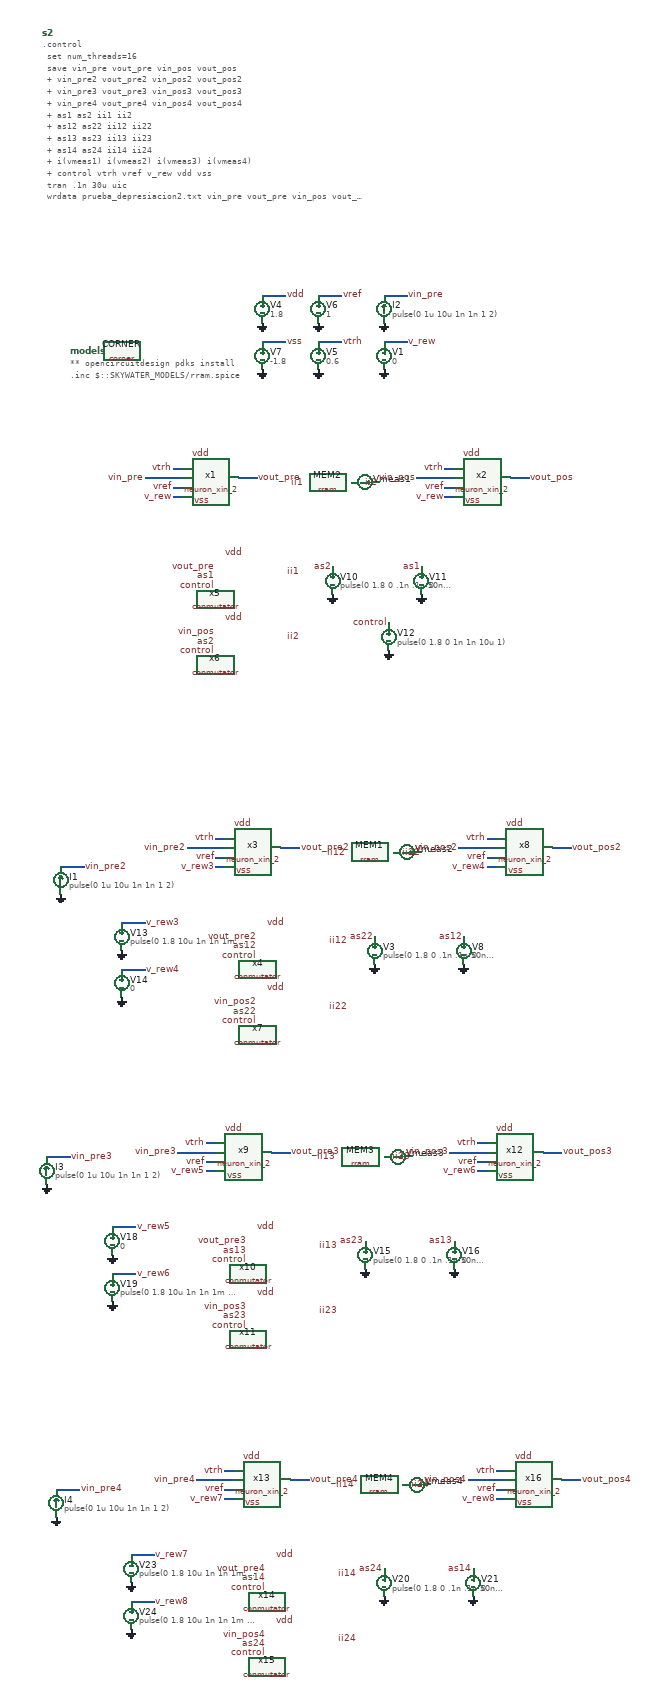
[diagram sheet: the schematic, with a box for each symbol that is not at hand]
v {xschem version=3.4.5 file_version=1.2
}
G {}
K {}
V {}
S {}
E {}
B 2 -2720 -470 -2300 -270 {flags=graph
y1=0
y2=1.8
ypos1=0
ypos2=2
divy=5
subdivy=1
unity=1
x1=1e-12
x2=3e-05
divx=5
subdivx=1
xlabmag=1.0
ylabmag=1.0
node="control
vtrh
vrew"
color="4 6 7"
dataset=-1
unitx=1
logx=0
logy=0
}
B 2 -2720 -270 -2300 -70 {flags=graph
y1=0
y2=0.01
ypos1=0
ypos2=2
divy=5
subdivy=1
unity=1
x1=1e-12
x2=3e-05
divx=5
subdivx=1
xlabmag=1.0
ylabmag=1.0
node=v_rew
color=7
dataset=-1
unitx=1
logx=0
logy=0
}
B 2 -2720 -70 -2300 130 {flags=graph
y1=0
y2=3
ypos1=0
ypos2=2
divy=5
subdivy=1
unity=1
x1=1e-12
x2=3e-05
divx=5
subdivx=1
xlabmag=1.0
ylabmag=1.0
node="as1
as2"
color="4 7"
dataset=-1
unitx=1
logx=0
logy=0
}
B 2 -1960 70 -1540 270 {flags=graph
y1=-1.2e-06
y2=7.4e-07
ypos1=0
ypos2=2
divy=5
subdivy=1
unity=1
x1=1e-12
x2=3e-05
divx=5
subdivx=1
xlabmag=1.0
ylabmag=1.0


dataset=-1
unitx=1
logx=0
logy=0


color=8
node=I(vmeas1)}
B 2 -1220 -130 -420 270 {flags=graph
y1=48e3
y2=56e3
ypos1=0
ypos2=2
divy=5
subdivy=1
unity=1
x1=1e-12
x2=3e-05
divx=5
subdivx=1
xlabmag=1.0
ylabmag=1.0


dataset=-1
unitx=1
logx=0
logy=0







color=9
node="\\"ii1 ii2 - i(vmeas1) /\\""
linewidth_mult=2}
B 2 -1220 -930 -420 -530 {flags=graph
y1=0
y2=1.8
ypos1=0
ypos2=2
divy=5
subdivy=1
unity=1

x2=3e-05
divx=5
subdivx=1
xlabmag=1.0
ylabmag=1.0
node=vout_pre
color=4
dataset=-1
unitx=1
logx=0
logy=0

x1=1e-12
linewidth_mult=2}
B 2 -1220 -530 -420 -130 {flags=graph

y2=1.8
ypos1=0
ypos2=2
divy=5
subdivy=1
unity=1

x2=3e-05
divx=5
subdivx=1
xlabmag=1.0
ylabmag=1.0
node=vout_pos
color=4
dataset=-1
unitx=1
logx=0
logy=0

y1=0
linewidth_mult=2
x1=1e-12}
B 2 -420 -130 380 270 {flags=graph
y1=48e3
y2=56e3
ypos1=0
ypos2=2
divy=5
subdivy=1
unity=1

x2=3e-05
divx=5
subdivx=1
xlabmag=1.0
ylabmag=1.0


dataset=-1
unitx=1
logx=0
logy=0







color=9
node="\\"ii12 ii22 - i(vmeas2) /\\""
linewidth_mult=2
x1=1e-12}
B 2 -420 -930 380 -530 {flags=graph
y1=0.44
y2=1.7
ypos1=0
ypos2=2
divy=5
subdivy=1
unity=1

x2=3e-05
divx=5
subdivx=1
xlabmag=1.0
ylabmag=1.0
node=vout_pre2
color=4
dataset=-1
unitx=1
logx=0
logy=0

x1=1e-12
linewidth_mult=2}
B 2 -420 -530 380 -130 {flags=graph

y2=1.8
ypos1=0
ypos2=2
divy=5
subdivy=1
unity=1

x2=3e-05
divx=5
subdivx=1
xlabmag=1.0
ylabmag=1.0
node=vout_pos2
color=4
dataset=-1
unitx=1
logx=0
logy=0

y1=0
linewidth_mult=2
x1=1e-12}
B 2 380 -130 1180 270 {flags=graph
y1=48e3
y2=56e3
ypos1=0
ypos2=2
divy=5
subdivy=1
unity=1
x1=1e-12
x2=3e-05
divx=5
subdivx=1
xlabmag=1.0
ylabmag=1.0


dataset=-1
unitx=1
logx=0
logy=0







color=9
node="\\"ii13 ii23 - i(vmeas3) /\\""
linewidth_mult=2}
B 2 380 -930 1180 -530 {flags=graph
y1=0
y2=1.8
ypos1=0
ypos2=2
divy=5
subdivy=1
unity=1

x2=3e-05
divx=5
subdivx=1
xlabmag=1.0
ylabmag=1.0
node=vout_pre3
color=4
dataset=-1
unitx=1
logx=0
logy=0

x1=1e-12
linewidth_mult=2}
B 2 380 -530 1180 -130 {flags=graph

y2=1.8
ypos1=0
ypos2=2
divy=5
subdivy=1
unity=1

x2=3e-05
divx=5
subdivx=1
xlabmag=1.0
ylabmag=1.0
node=vout_pos3
color=4
dataset=-1
unitx=1
logx=0
logy=0

y1=0
linewidth_mult=2
x1=1e-12}
B 2 1180 -130 1980 270 {flags=graph
y1=48e3
y2=56e3
ypos1=0
ypos2=2
divy=5
subdivy=1
unity=1
x1=1e-12
x2=3e-05
divx=5
subdivx=1
xlabmag=1.0
ylabmag=1.0


dataset=-1
unitx=1
logx=0
logy=0







color=9
node="\\"ii14 ii24 - i(vmeas4) /\\""
linewidth_mult=2}
B 2 1180 -930 1980 -530 {flags=graph
y1=0
y2=1.8
ypos1=0
ypos2=2
divy=5
subdivy=1
unity=1

x2=3e-05
divx=5
subdivx=1
xlabmag=1.0
ylabmag=1.0
node=vout_pre4
color=4
dataset=-1
unitx=1
logx=0
logy=0

x1=1e-12
linewidth_mult=2}
B 2 1180 -530 1980 -130 {flags=graph

y2=1.8
ypos1=0
ypos2=2
divy=5
subdivy=1
unity=1

x2=3e-05
divx=5
subdivx=1
xlabmag=1.0
ylabmag=1.0
node=vout_pos4
color=4
dataset=-1
unitx=1
logx=0
logy=0

y1=0
linewidth_mult=2
x1=1e-12}
N -2130 -320 -2110 -320 {
lab=vref}
N -1940 -730 -1890 -730 {
lab=vdd}
N -1820 -630 -1770 -630 {
lab=vtrh}
N -1820 -730 -1770 -730 {
lab=vref}
N -1940 -630 -1890 -630 {
lab=vss}
N -1680 -630 -1630 -630 {
lab=v_rew}
N -2130 -360 -2110 -360 {
lab=vtrh}
N -2130 -300 -2110 -300 {
lab=v_rew}
N -2190 -340 -2110 -340 {
lab=vin_pre}
N -1990 -340 -1950 -340 {
lab=vout_pre}
N -1550 -320 -1530 -320 {
lab=vref}
N -1550 -360 -1530 -360 {
lab=vtrh}
N -1550 -300 -1530 -300 {
lab=v_rew}
N -1610 -340 -1530 -340 {
lab=vin_pos}
N -1410 -340 -1370 -340 {
lab=vout_pos}
N -1680 -730 -1630 -730 {
lab=vin_pre}
N -2040 470 -2020 470 {
lab=vref}
N -2040 430 -2020 430 {
lab=vtrh}
N -2040 490 -2020 490 {
lab=v_rew3}
N -2100 450 -2020 450 {
lab=vin_pre2}
N -1900 450 -1860 450 {
lab=vout_pre2}
N -1460 470 -1440 470 {
lab=vref}
N -1460 430 -1440 430 {
lab=vtrh}
N -1460 490 -1440 490 {
lab=v_rew4}
N -1520 450 -1440 450 {
lab=vin_pos2}
N -1320 450 -1280 450 {
lab=vout_pos2}
N -2240 610 -2190 610 {
lab=v_rew3}
N -2240 710 -2190 710 {
lab=v_rew4}
N -2060 1120 -2040 1120 {
lab=vref}
N -2060 1080 -2040 1080 {
lab=vtrh}
N -2060 1140 -2040 1140 {
lab=v_rew5}
N -2120 1100 -2040 1100 {
lab=vin_pre3}
N -1920 1100 -1880 1100 {
lab=vout_pre3}
N -1480 1120 -1460 1120 {
lab=vref}
N -1480 1080 -1460 1080 {
lab=vtrh}
N -1480 1140 -1460 1140 {
lab=v_rew6}
N -1540 1100 -1460 1100 {
lab=vin_pos3}
N -1340 1100 -1300 1100 {
lab=vout_pos3}
N -2260 1260 -2210 1260 {
lab=v_rew5}
N -2260 1360 -2210 1360 {
lab=v_rew6}
N -2020 1820 -2000 1820 {
lab=vref}
N -2020 1780 -2000 1780 {
lab=vtrh}
N -2020 1840 -2000 1840 {
lab=v_rew7}
N -2080 1800 -2000 1800 {
lab=vin_pre4}
N -1880 1800 -1840 1800 {
lab=vout_pre4}
N -1440 1820 -1420 1820 {
lab=vref}
N -1440 1780 -1420 1780 {
lab=vtrh}
N -1440 1840 -1420 1840 {
lab=v_rew8}
N -1500 1800 -1420 1800 {
lab=vin_pos4}
N -1300 1800 -1260 1800 {
lab=vout_pos4}
N -2220 1960 -2170 1960 {
lab=v_rew7}
N -2220 2060 -2170 2060 {
lab=v_rew8}
N -2370 490 -2320 490 {
lab=vin_pre2}
N -2400 1110 -2350 1110 {
lab=vin_pre3}
N -2380 1820 -2330 1820 {
lab=vin_pre4}
C {/home/user/Documentos/neuron_xin_2.sym} -2050 -340 0 0 {name=x1}
C {devices/code_shown.sym} -2410 -1290 0 0 {name=s2 only_toplevel=false value="
.control
 set num_threads=16
 save vin_pre vout_pre vin_pos vout_pos
 + vin_pre2 vout_pre2 vin_pos2 vout_pos2
 + vin_pre3 vout_pre3 vin_pos3 vout_pos3
 + vin_pre4 vout_pre4 vin_pos4 vout_pos4
 + as1  as2  ii1  ii2
 + as12 as22 ii12 ii22
 + as13 as23 ii13 ii23
 + as14 as24 ii14 ii24
 + i(vmeas1) i(vmeas2) i(vmeas3) i(vmeas4)
 + control vtrh vref v_rew vdd vss
 tran .1n 30u uic
 wrdata prueba_depresiacion2.txt vin_pre vout_pre vin_pos vout_pos
 + vin_pre2 vout_pre2 vin_pos2 vout_pos2
 + vin_pre3 vout_pre3 vin_pos3 vout_pos3
 + vin_pre4 vout_pre4 vin_pos4 vout_pos4
 + as1  as2  ii1  ii2
 + as12 as22 ii12 ii22
 + as13 as23 ii13 ii23
 + as14 as24 ii14 ii24
 + i(vmeas1) i(vmeas2) i(vmeas3) i(vmeas4)
 write prueba_rewNeuron_depresiacion2.raw
.endc


" }
C {devices/lab_wire.sym} -2130 -320 0 0 {name=p54 sig_type=std_logic lab=vref}
C {devices/lab_wire.sym} -2050 -390 0 0 {name=p56 sig_type=std_logic lab=vdd}
C {devices/vsource.sym} -1940 -700 0 0 {name=V4 value=1.8}
C {devices/gnd.sym} -1940 -670 0 0 {name=l9 lab=GND}
C {devices/lab_wire.sym} -1890 -730 0 1 {name=p61 sig_type=std_logic lab=vdd}
C {devices/vsource.sym} -1820 -600 0 0 {name=V5 value=0.6}
C {devices/gnd.sym} -1820 -570 0 0 {name=l10 lab=GND}
C {devices/lab_wire.sym} -1770 -630 0 1 {name=p63 sig_type=std_logic lab=vtrh}
C {devices/vsource.sym} -1820 -700 0 0 {name=V6 value=1}
C {devices/gnd.sym} -1820 -670 0 0 {name=l11 lab=GND}
C {devices/lab_wire.sym} -1770 -730 0 1 {name=p64 sig_type=std_logic lab=vref}
C {devices/lab_wire.sym} -1950 -340 0 1 {name=p70 sig_type=std_logic lab=vout_pre}
C {devices/vsource.sym} -1940 -600 0 0 {name=V7 value=-1.8}
C {devices/gnd.sym} -1940 -570 0 0 {name=l13 lab=GND}
C {devices/lab_wire.sym} -1890 -630 0 1 {name=p72 sig_type=std_logic lab=vss}
C {devices/vsource.sym} -1680 -600 0 0 {name=V1 value=0}
C {devices/gnd.sym} -1680 -570 0 0 {name=l2 lab=GND}
C {devices/lab_wire.sym} -1630 -630 0 1 {name=p5 sig_type=std_logic lab=v_rew}
C {devices/lab_wire.sym} -2190 -340 0 0 {name=p7 sig_type=std_logic lab=vin_pre}
C {devices/lab_wire.sym} -2130 -360 0 0 {name=p8 sig_type=std_logic lab=vtrh}
C {devices/lab_wire.sym} -2050 -290 2 1 {name=p9 sig_type=std_logic lab=vss}
C {devices/lab_wire.sym} -2130 -300 0 0 {name=p1 sig_type=std_logic lab=v_rew}
C {sky130_fd_pr/corner.sym} -2240 -610 0 0 {name=CORNER only_toplevel=true corner=tt}
C {devices/code.sym} -2350 -610 0 0 {name=models
only_toplevel=false
format ="tcleval( @value ) "
value="** opencircuitdesign pdks install
.inc $::SKYWATER_MODELS/rram.spice"
spice_ignore=false}
C {devices/gnd.sym} -1790 -90 0 0 {name=l7 lab=GND}
C {devices/vsource.sym} -1790 -120 0 0 {name=V10 value="pulse(0 1.8 0 .1n .1n 50n 100n 100)"}
C {devices/gnd.sym} -1600 -90 0 0 {name=l12 lab=GND}
C {devices/vsource.sym} -1600 -120 0 0 {name=V11 value=0}
C {devices/gnd.sym} -1670 30 0 0 {name=l14 lab=GND}
C {devices/vsource.sym} -1670 0 0 0 {name=V12 value="pulse(0 1.8 0 1n 1n 10u 1)"}
C {devices/lab_wire.sym} -1670 -30 0 0 {name=p32 sig_type=std_logic lab=control
}
C {/home/user/Documentos/conmutator.sym} -2040 -80 0 0 {name=x5}
C {devices/lab_wire.sym} -2040 -110 0 0 {name=p33 sig_type=std_logic lab=control
}
C {devices/lab_wire.sym} -2040 -150 0 0 {name=p34 sig_type=std_logic lab=vout_pre}
C {devices/lab_wire.sym} -2040 -130 0 0 {name=p35 sig_type=std_logic lab=as1
}
C {devices/lab_wire.sym} -1980 -180 0 0 {name=p36 sig_type=std_logic lab=vdd}
C {devices/lab_wire.sym} -1890 -140 0 1 {name=p37 sig_type=std_logic lab=ii1}
C {devices/lab_wire.sym} -1600 -150 0 0 {name=p39 sig_type=std_logic lab=as1
}
C {devices/lab_wire.sym} -1790 -150 0 0 {name=p41 sig_type=std_logic lab=as2
}
C {/home/user/Documentos/conmutator.sym} -2040 60 0 0 {name=x6}
C {devices/lab_wire.sym} -2040 30 0 0 {name=p42 sig_type=std_logic lab=control
}
C {devices/lab_wire.sym} -2040 -10 0 0 {name=p43 sig_type=std_logic lab=vin_pos}
C {devices/lab_wire.sym} -2040 10 0 0 {name=p44 sig_type=std_logic lab=as2}
C {devices/lab_wire.sym} -1980 -40 0 0 {name=p45 sig_type=std_logic lab=vdd}
C {devices/lab_wire.sym} -1890 0 0 1 {name=p46 sig_type=std_logic lab=ii2}
C {sky130_fd_pr/rram.sym} -1800 -330 3 0 {name=MEM2
model=rram
spiceprefix=X}
C {devices/ammeter.sym} -1720 -330 3 1 {name=Vmeas1 savecurrent=true spice_ignore=0}
C {devices/lab_wire.sym} -1850 -330 0 0 {name=p67 sig_type=std_logic lab=ii1}
C {devices/lab_wire.sym} -1690 -330 0 0 {name=p68 sig_type=std_logic lab=ii2}
C {/home/user/Documentos/neuron_xin_2.sym} -1470 -340 0 0 {name=x2}
C {devices/lab_wire.sym} -1550 -320 0 0 {name=p2 sig_type=std_logic lab=vref}
C {devices/lab_wire.sym} -1470 -390 0 0 {name=p3 sig_type=std_logic lab=vdd}
C {devices/lab_wire.sym} -1370 -340 0 1 {name=p4 sig_type=std_logic lab=vout_pos}
C {devices/lab_wire.sym} -1610 -340 0 0 {name=p6 sig_type=std_logic lab=vin_pos}
C {devices/lab_wire.sym} -1550 -360 0 0 {name=p10 sig_type=std_logic lab=vtrh}
C {devices/lab_wire.sym} -1470 -290 2 1 {name=p11 sig_type=std_logic lab=vss}
C {devices/lab_wire.sym} -1550 -300 0 0 {name=p12 sig_type=std_logic lab=v_rew}
C {devices/gnd.sym} -1680 -670 0 0 {name=l15 lab=GND}
C {devices/lab_wire.sym} -1630 -730 0 1 {name=p85 sig_type=std_logic lab=vin_pre}
C {devices/isource.sym} -1680 -700 2 1 {name=I2 value="pulse(0 1u 10u 1n 1n 1 2)" }
C {/home/user/Documentos/neuron_xin_2.sym} -1960 450 0 0 {name=x3}
C {devices/lab_wire.sym} -2040 470 0 0 {name=p14 sig_type=std_logic lab=vref}
C {devices/lab_wire.sym} -1960 400 0 0 {name=p15 sig_type=std_logic lab=vdd}
C {devices/lab_wire.sym} -1860 450 0 1 {name=p16 sig_type=std_logic lab=vout_pre2}
C {devices/lab_wire.sym} -2100 450 0 0 {name=p17 sig_type=std_logic lab=vin_pre2}
C {devices/lab_wire.sym} -2040 430 0 0 {name=p18 sig_type=std_logic lab=vtrh}
C {devices/lab_wire.sym} -1960 500 2 1 {name=p19 sig_type=std_logic lab=vss}
C {devices/lab_wire.sym} -2040 490 0 0 {name=p20 sig_type=std_logic lab=v_rew3}
C {devices/gnd.sym} -1700 700 0 0 {name=l3 lab=GND}
C {devices/vsource.sym} -1700 670 0 0 {name=V3 value="pulse(0 1.8 0 .1n .1n 50n 100n 100)"}
C {devices/gnd.sym} -1510 700 0 0 {name=l4 lab=GND}
C {devices/vsource.sym} -1510 670 0 0 {name=V8 value=0}
C {/home/user/Documentos/conmutator.sym} -1950 710 0 0 {name=x4}
C {devices/lab_wire.sym} -1950 680 0 0 {name=p22 sig_type=std_logic lab=control
}
C {devices/lab_wire.sym} -1950 640 0 0 {name=p23 sig_type=std_logic lab=vout_pre2}
C {devices/lab_wire.sym} -1950 660 0 0 {name=p24 sig_type=std_logic lab=as12
}
C {devices/lab_wire.sym} -1890 610 0 0 {name=p25 sig_type=std_logic lab=vdd}
C {devices/lab_wire.sym} -1800 650 0 1 {name=p26 sig_type=std_logic lab=ii12}
C {devices/lab_wire.sym} -1510 640 0 0 {name=p27 sig_type=std_logic lab=as12
}
C {devices/lab_wire.sym} -1700 640 0 0 {name=p28 sig_type=std_logic lab=as22
}
C {/home/user/Documentos/conmutator.sym} -1950 850 0 0 {name=x7}
C {devices/lab_wire.sym} -1950 820 0 0 {name=p29 sig_type=std_logic lab=control
}
C {devices/lab_wire.sym} -1950 780 0 0 {name=p30 sig_type=std_logic lab=vin_pos2}
C {devices/lab_wire.sym} -1950 800 0 0 {name=p31 sig_type=std_logic lab=as22}
C {devices/lab_wire.sym} -1890 750 0 0 {name=p38 sig_type=std_logic lab=vdd}
C {devices/lab_wire.sym} -1800 790 0 1 {name=p40 sig_type=std_logic lab=ii22}
C {sky130_fd_pr/rram.sym} -1710 460 3 1 {name=MEM1
model=rram
spiceprefix=X}
C {devices/ammeter.sym} -1630 460 3 1 {name=Vmeas2 savecurrent=true spice_ignore=0}
C {devices/lab_wire.sym} -1760 460 0 0 {name=p47 sig_type=std_logic lab=ii12}
C {devices/lab_wire.sym} -1600 460 0 0 {name=p48 sig_type=std_logic lab=ii22}
C {/home/user/Documentos/neuron_xin_2.sym} -1380 450 0 0 {name=x8}
C {devices/lab_wire.sym} -1460 470 0 0 {name=p49 sig_type=std_logic lab=vref}
C {devices/lab_wire.sym} -1380 400 0 0 {name=p50 sig_type=std_logic lab=vdd}
C {devices/lab_wire.sym} -1280 450 0 1 {name=p51 sig_type=std_logic lab=vout_pos2}
C {devices/lab_wire.sym} -1520 450 0 0 {name=p52 sig_type=std_logic lab=vin_pos2}
C {devices/lab_wire.sym} -1460 430 0 0 {name=p53 sig_type=std_logic lab=vtrh}
C {devices/lab_wire.sym} -1380 500 2 1 {name=p55 sig_type=std_logic lab=vss}
C {devices/lab_wire.sym} -1460 490 0 0 {name=p57 sig_type=std_logic lab=v_rew4}
C {devices/vsource.sym} -2240 640 0 0 {name=V13 value="pulse(0 1.8 10u 1n 1n 1m 2m)"}
C {devices/gnd.sym} -2240 670 0 0 {name=l6 lab=GND}
C {devices/lab_wire.sym} -2190 610 0 1 {name=p58 sig_type=std_logic lab=v_rew3}
C {devices/vsource.sym} -2240 740 0 0 {name=V14 value=0}
C {devices/gnd.sym} -2240 770 0 0 {name=l8 lab=GND}
C {devices/lab_wire.sym} -2190 710 0 1 {name=p59 sig_type=std_logic lab=v_rew4}
C {/home/user/Documentos/neuron_xin_2.sym} -1980 1100 0 0 {name=x9}
C {devices/lab_wire.sym} -2060 1120 0 0 {name=p60 sig_type=std_logic lab=vref}
C {devices/lab_wire.sym} -1980 1050 0 0 {name=p62 sig_type=std_logic lab=vdd}
C {devices/lab_wire.sym} -1880 1100 0 1 {name=p65 sig_type=std_logic lab=vout_pre3}
C {devices/lab_wire.sym} -2120 1100 0 0 {name=p66 sig_type=std_logic lab=vin_pre3}
C {devices/lab_wire.sym} -2060 1080 0 0 {name=p69 sig_type=std_logic lab=vtrh}
C {devices/lab_wire.sym} -1980 1150 2 1 {name=p71 sig_type=std_logic lab=vss}
C {devices/lab_wire.sym} -2060 1140 0 0 {name=p73 sig_type=std_logic lab=v_rew5}
C {devices/gnd.sym} -1720 1350 0 0 {name=l16 lab=GND}
C {devices/vsource.sym} -1720 1320 0 0 {name=V15 value="pulse(0 1.8 0 .1n .1n 50n 100n 100)"}
C {devices/gnd.sym} -1530 1350 0 0 {name=l17 lab=GND}
C {devices/vsource.sym} -1530 1320 0 0 {name=V16 value=0}
C {/home/user/Documentos/conmutator.sym} -1970 1360 0 0 {name=x10}
C {devices/lab_wire.sym} -1970 1330 0 0 {name=p75 sig_type=std_logic lab=control
}
C {devices/lab_wire.sym} -1970 1290 0 0 {name=p76 sig_type=std_logic lab=vout_pre3}
C {devices/lab_wire.sym} -1970 1310 0 0 {name=p77 sig_type=std_logic lab=as13
}
C {devices/lab_wire.sym} -1910 1260 0 0 {name=p78 sig_type=std_logic lab=vdd}
C {devices/lab_wire.sym} -1820 1300 0 1 {name=p79 sig_type=std_logic lab=ii13}
C {devices/lab_wire.sym} -1530 1290 0 0 {name=p80 sig_type=std_logic lab=as13}
C {devices/lab_wire.sym} -1720 1290 0 0 {name=p81 sig_type=std_logic lab=as23
}
C {/home/user/Documentos/conmutator.sym} -1970 1500 0 0 {name=x11}
C {devices/lab_wire.sym} -1970 1470 0 0 {name=p82 sig_type=std_logic lab=control
}
C {devices/lab_wire.sym} -1970 1430 0 0 {name=p83 sig_type=std_logic lab=vin_pos3}
C {devices/lab_wire.sym} -1970 1450 0 0 {name=p84 sig_type=std_logic lab=as23}
C {devices/lab_wire.sym} -1910 1400 0 0 {name=p86 sig_type=std_logic lab=vdd}
C {devices/lab_wire.sym} -1820 1440 0 1 {name=p87 sig_type=std_logic lab=ii23}
C {sky130_fd_pr/rram.sym} -1730 1110 3 1 {name=MEM3
model=rram
spiceprefix=X}
C {devices/ammeter.sym} -1650 1110 3 1 {name=Vmeas3 savecurrent=true spice_ignore=0}
C {devices/lab_wire.sym} -1780 1110 0 0 {name=p88 sig_type=std_logic lab=ii13}
C {devices/lab_wire.sym} -1620 1110 0 0 {name=p89 sig_type=std_logic lab=ii23}
C {/home/user/Documentos/neuron_xin_2.sym} -1400 1100 0 0 {name=x12}
C {devices/lab_wire.sym} -1480 1120 0 0 {name=p90 sig_type=std_logic lab=vref}
C {devices/lab_wire.sym} -1400 1050 0 0 {name=p91 sig_type=std_logic lab=vdd}
C {devices/lab_wire.sym} -1300 1100 0 1 {name=p92 sig_type=std_logic lab=vout_pos3}
C {devices/lab_wire.sym} -1540 1100 0 0 {name=p93 sig_type=std_logic lab=vin_pos3}
C {devices/lab_wire.sym} -1480 1080 0 0 {name=p94 sig_type=std_logic lab=vtrh}
C {devices/lab_wire.sym} -1400 1150 2 1 {name=p95 sig_type=std_logic lab=vss}
C {devices/lab_wire.sym} -1480 1140 0 0 {name=p96 sig_type=std_logic lab=v_rew6}
C {devices/vsource.sym} -2260 1290 0 0 {name=V18 value=0}
C {devices/gnd.sym} -2260 1320 0 0 {name=l19 lab=GND}
C {devices/lab_wire.sym} -2210 1260 0 1 {name=p97 sig_type=std_logic lab=v_rew5}
C {devices/vsource.sym} -2260 1390 0 0 {name=V19 value="pulse(0 1.8 10u 1n 1n 1m 2m)"}
C {devices/gnd.sym} -2260 1420 0 0 {name=l20 lab=GND}
C {devices/lab_wire.sym} -2210 1360 0 1 {name=p98 sig_type=std_logic lab=v_rew6}
C {/home/user/Documentos/neuron_xin_2.sym} -1940 1800 0 0 {name=x13}
C {devices/lab_wire.sym} -2020 1820 0 0 {name=p99 sig_type=std_logic lab=vref}
C {devices/lab_wire.sym} -1940 1750 0 0 {name=p100 sig_type=std_logic lab=vdd}
C {devices/lab_wire.sym} -1840 1800 0 1 {name=p101 sig_type=std_logic lab=vout_pre4}
C {devices/lab_wire.sym} -2080 1800 0 0 {name=p102 sig_type=std_logic lab=vin_pre4}
C {devices/lab_wire.sym} -2020 1780 0 0 {name=p103 sig_type=std_logic lab=vtrh}
C {devices/lab_wire.sym} -1940 1850 2 1 {name=p104 sig_type=std_logic lab=vss}
C {devices/lab_wire.sym} -2020 1840 0 0 {name=p105 sig_type=std_logic lab=v_rew7}
C {devices/gnd.sym} -1680 2050 0 0 {name=l21 lab=GND}
C {devices/vsource.sym} -1680 2020 0 0 {name=V20 value="pulse(0 1.8 0 .1n .1n 50n 100n 100)"}
C {devices/gnd.sym} -1490 2050 0 0 {name=l22 lab=GND}
C {devices/vsource.sym} -1490 2020 0 0 {name=V21 value=0}
C {/home/user/Documentos/conmutator.sym} -1930 2060 0 0 {name=x14}
C {devices/lab_wire.sym} -1930 2030 0 0 {name=p107 sig_type=std_logic lab=control
}
C {devices/lab_wire.sym} -1930 1990 0 0 {name=p108 sig_type=std_logic lab=vout_pre4}
C {devices/lab_wire.sym} -1930 2010 0 0 {name=p109 sig_type=std_logic lab=as14
}
C {devices/lab_wire.sym} -1870 1960 0 0 {name=p110 sig_type=std_logic lab=vdd}
C {devices/lab_wire.sym} -1780 2000 0 1 {name=p111 sig_type=std_logic lab=ii14}
C {devices/lab_wire.sym} -1490 1990 0 0 {name=p112 sig_type=std_logic lab=as14
}
C {devices/lab_wire.sym} -1680 1990 0 0 {name=p113 sig_type=std_logic lab=as24
}
C {/home/user/Documentos/conmutator.sym} -1930 2200 0 0 {name=x15}
C {devices/lab_wire.sym} -1930 2170 0 0 {name=p114 sig_type=std_logic lab=control
}
C {devices/lab_wire.sym} -1930 2130 0 0 {name=p115 sig_type=std_logic lab=vin_pos4}
C {devices/lab_wire.sym} -1930 2150 0 0 {name=p116 sig_type=std_logic lab=as24}
C {devices/lab_wire.sym} -1870 2100 0 0 {name=p117 sig_type=std_logic lab=vdd}
C {devices/lab_wire.sym} -1780 2140 0 1 {name=p118 sig_type=std_logic lab=ii24}
C {sky130_fd_pr/rram.sym} -1690 1810 3 1 {name=MEM4
model=rram
spiceprefix=X}
C {devices/ammeter.sym} -1610 1810 3 1 {name=Vmeas4 savecurrent=true spice_ignore=0}
C {devices/lab_wire.sym} -1740 1810 0 0 {name=p119 sig_type=std_logic lab=ii14}
C {devices/lab_wire.sym} -1580 1810 0 0 {name=p120 sig_type=std_logic lab=ii24}
C {/home/user/Documentos/neuron_xin_2.sym} -1360 1800 0 0 {name=x16}
C {devices/lab_wire.sym} -1440 1820 0 0 {name=p121 sig_type=std_logic lab=vref}
C {devices/lab_wire.sym} -1360 1750 0 0 {name=p122 sig_type=std_logic lab=vdd}
C {devices/lab_wire.sym} -1260 1800 0 1 {name=p123 sig_type=std_logic lab=vout_pos4}
C {devices/lab_wire.sym} -1500 1800 0 0 {name=p124 sig_type=std_logic lab=vin_pos4}
C {devices/lab_wire.sym} -1440 1780 0 0 {name=p125 sig_type=std_logic lab=vtrh}
C {devices/lab_wire.sym} -1360 1850 2 1 {name=p126 sig_type=std_logic lab=vss}
C {devices/lab_wire.sym} -1440 1840 0 0 {name=p127 sig_type=std_logic lab=v_rew8}
C {devices/vsource.sym} -2220 1990 0 0 {name=V23 value="pulse(0 1.8 10u 1n 1n 1m 2m)"}
C {devices/gnd.sym} -2220 2020 0 0 {name=l24 lab=GND}
C {devices/lab_wire.sym} -2170 1960 0 1 {name=p128 sig_type=std_logic lab=v_rew7}
C {devices/vsource.sym} -2220 2090 0 0 {name=V24 value="pulse(0 1.8 10u 1n 1n 1m 2m)"}
C {devices/gnd.sym} -2220 2120 0 0 {name=l25 lab=GND}
C {devices/lab_wire.sym} -2170 2060 0 1 {name=p129 sig_type=std_logic lab=v_rew8}
C {devices/gnd.sym} -2370 550 0 0 {name=l5 lab=GND}
C {devices/lab_wire.sym} -2320 490 0 1 {name=p21 sig_type=std_logic lab=vin_pre2}
C {devices/isource.sym} -2370 520 2 1 {name=I1 value="pulse(0 1u 10u 1n 1n 1 2)" }
C {devices/gnd.sym} -2400 1170 0 0 {name=l18 lab=GND}
C {devices/lab_wire.sym} -2350 1110 0 1 {name=p74 sig_type=std_logic lab=vin_pre3}
C {devices/isource.sym} -2400 1140 2 1 {name=I3 value="pulse(0 1u 10u 1n 1n 1 2)" }
C {devices/gnd.sym} -2380 1880 0 0 {name=l23 lab=GND}
C {devices/lab_wire.sym} -2330 1820 0 1 {name=p106 sig_type=std_logic lab=vin_pre4}
C {devices/isource.sym} -2380 1850 2 1 {name=I4 value="pulse(0 1u 10u 1n 1n 1 2)" }
